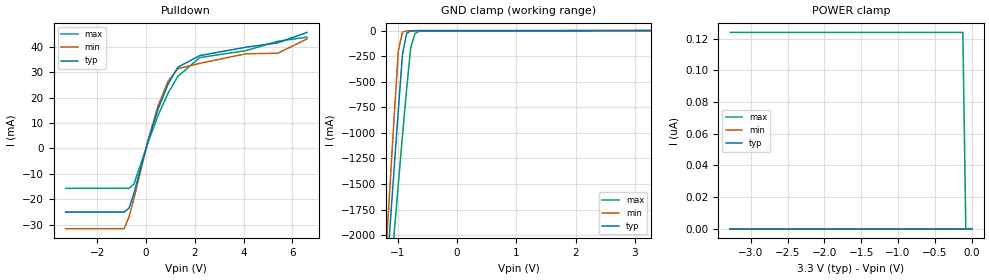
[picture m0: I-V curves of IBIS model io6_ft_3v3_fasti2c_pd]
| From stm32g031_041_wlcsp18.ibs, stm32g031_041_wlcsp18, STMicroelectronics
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[Model]  io6_ft_3v3_fasti2c_pd
Model_type I/O_open_drain
Polarity   Non-Inverting
Enable   Active-Low
Vinl =   0.990000V
Vinh =   2.310000V
Vmeas =  1.650000V
Cref =   50.000000pF
Rref =   500
Vref =   3.0V
C_comp   1.290400pF   1.272500pF   1.305600pF
[Temperature Range]   25.000000   -40.000000   0.125000k
[Pullup Reference]   3.300000V   3.000000V   3.600000V
[Pulldown Reference]   0.0V   0.0V   0.0V
[POWER Clamp Reference]   3.300000V   3.000000V   3.600000V
[GND Clamp Reference]   0.0V   0.0V   0.0V
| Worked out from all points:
|   slope of the pulldown table from 0 to 0.495 V, typ, clamps not added: 31.8 ohm
|   GND clamp passes 1 mA (typ) near -0.65 V on its own axis
[Pulldown]
|Voltage   I(typ)   I(min)   I(max)
-3.3V     -25.03mA   -31.54mA   -15.7mA
-900mV    -25.03mA   -31.54mA   -15.7mA
-700mV    -23.48mA   -26.95mA   -15.7mA
-500mV    -17.69mA   -19.75mA   -14.07mA
100mV     3.479mA    3.853mA    2.862mA
500mV     15.71mA    16.96mA    13.17mA
900mV     25.22mA    26.33mA    21.66mA
1.3V      31.91mA    31.32mA    28.29mA
2.2V      36.48mA    33.43mA    35.69mA
4.1V      39.78mA    37.21mA    38.43mA
5.4V      41.49mA    37.39mA    42.11mA
6.6V      45.6mA     43.05mA    43.74mA
[GND_clamp]
|Voltage   I(typ)   I(min)   I(max)
-3.3V     -9.61A     -9.635A    -9.699A
-1.2V     -2.493A    -2.184A    -2.958A
-1.13V    -1.917A    -1.512A    -2.469A
-1.06V    -1.345A    -845.6mA   -1.983A
-990mV    -779.8mA   -200.2mA   -1.503A
-920mV    -235.6mA   -14.2mA    -1.03A
-850mV    -26.08mA   -3.351mA   -574.2mA
-780mV    -4.512mA   -1.821mA   -166.4mA
-710mV    -1.735mA   -881.8uA   -29.46mA
-640mV    -819.4uA   -295.6uA   -6.294mA
3.28V     86.85uA    64.2uA     109.1uA
[POWER_clamp]
|Voltage   I(typ)   I(min)   I(max)
-3.28V    0A         0A         124nA
-120mV    0A         0A         124nA
-80mV     0A         0A         0A
0V        0A         0A         0A
[Ramp]
| variable   typ   min   max
dV/dt_r  1.07274/2.09608n   0.96030/2.04067n   1.028/2.37778n
dV/dt_f  1.02906/1.87194n   0.94902/1.89195n   1.02288/1.93068n
R_load = 50.000000
